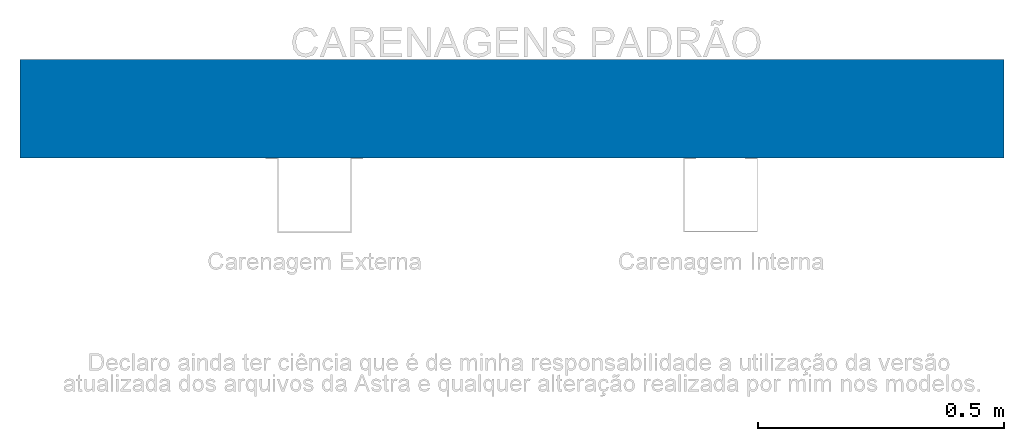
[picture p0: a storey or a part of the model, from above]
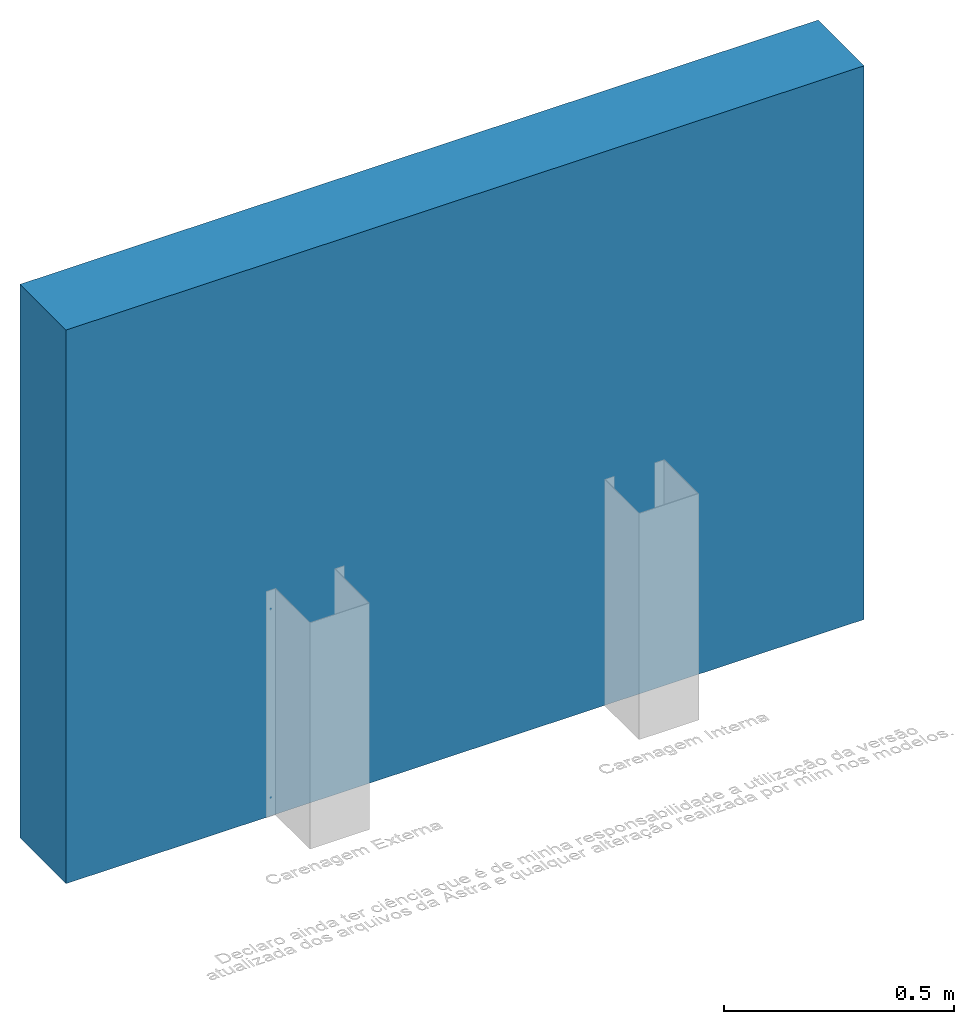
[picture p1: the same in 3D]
Properties of the parts of a building model (IFC2X3)

# File
Description: ViewDefinition [CoordinationView_V2.0]
File name: 0001
Time: 2025-07-10T16:41:57
Written by: The EXPRESS Data Manager Version 5.02.0100.07 : 28 Aug 2013
Made in: 21.0.0.383 - Exporter 21.0.0.383 - IU alternativa 21.0.0.383
Comment: STEP Physical File produced by: The EXPRESS Data Manager Version 5.02.0100.07 : 28 Aug 2013 * Module: EDMstepFileFactory/EDMstandAlone * Creation date: Thu Jul 10 16:41:57 2025 * Host: DNG1464 * Database: C:\Users\maria.cardoso\AppData\Local\Temp\3b02b41a-c4b6-4cdf-9117-29328b5b6a5f\55d656b9-dff8-46be-b086-2d08ecc8b85b\ifc * Database version: 5507 * Database creation date: Thu Jul 10 16:41:53 2025 * Schema: IFC2X3 * Model: DataRepository.ifc * Model creation date: Thu Jul 10 16:41:54 2025 * Header model: DataRepository.ifc_HeaderModel * Header model creation date: Thu Jul 10 16:41:54 2025 * EDMuser: sdai-user * EDMgroup: sdai-group * License ID and type: 5605 : Permanent license. Expiry date: * EDMstepFileFactory options: 020000

# IfcProject, 0001
LongName: Nome do projeto; Phase: Status do projeto

# IfcSite, Default
RefLatitude: -15, -52, 0, -120620; RefLongitude: -47, -55, 0, -114440; RefElevation: 0 mm

# IfcBuilding
Pset_BuildingCommon - NumberOfStoreys: 1

# IfcBuildingStorey: Nível:Cabeça de 8 mm, Vista Principal
LongName: Vista Principal; Elevation: 0 mm

# IfcBuildingElementProxy: Texto do modelo:600mm Arial (3)
In: Vista Principal
Type - Pset_BuildingElementProxyCommon - Reference: 600mm Arial
Type - Pset_QuantityTakeOff - Reference: 600mm Arial
Pset_BuildingElementProxyCommon - sets with these values: 2
Name (Texto do modelo:600mm Arial:...)
377453
377455
377750

# IfcBuildingElementProxy: Texto do modelo:TITULO, Texto do modelo:TITULO:377754
In: Vista Principal
Type - Pset_BuildingElementProxyCommon - Reference: TITULO
Type - Pset_QuantityTakeOff - Reference: TITULO
Pset_BuildingElementProxyCommon - sets with these values: 2
Pset_ProvisionForVoid - Shape: Undefined; Width: 150 mm; Depth: 150 mm

# IfcFlowTerminal: Carenagem - Aba Externa:Carenagem 600x150x150mm, Carenagem - Aba Externa:Carenagem 600x150x150mm:371474
In: Vista Principal
Type - Material: PS Branco
Type - Pset_ManufacturerTypeInformation - Manufacturer: Astra
Type - Pset_QuantityTakeOff - Reference: Carenagem 600x150x150mm
Pset_DistributionFlowElementCommon - Reference: Carenagem 600x150x150mm; sets with these values: 2

# IfcFlowTerminal: Carenagem - Aba Interna:Carenagem 600x150x150mm, Carenagem - Aba Interna:Carenagem 600x150x150mm:376178
In: Vista Principal
Type - Material: PS Branco
Type - Pset_ManufacturerTypeInformation - Manufacturer: Astra
Type - Pset_QuantityTakeOff - Reference: Carenagem 600x150x150mm
Pset_DistributionFlowElementCommon - Reference: Carenagem 600x150x150mm; sets with these values: 3
Pset_ManufacturerTypeInformation - sets with these values: 2

# IfcOpeningElement: Opening (4)
In: Vista Principal
Pset_ManufacturerTypeInformation - Manufacturer: Astra
Pset_OpeningElementCommon - Reference: Carenagem 600x150x150mm; sets with these values: 2
Name (Carenagem - Aba Externa:Carenagem 600x150x150mm:371474:...)
1
2
3
4

# IfcWallStandardCase: Parede básica:Genérico - 200 mm, Parede básica:Genérico - 200 mm:329028
In: Vista Principal
Type - PredefinedType: STANDARD; Material: Material pré-definido de parede 200 mm
Type - Pset_QuantityTakeOff - Reference: Genérico - 200 mm
Type - Pset_ReinforcementBarPitchOfWall - Reference: Genérico - 200 mm
Type - Pset_WallCommon - Reference: Genérico - 200 mm; IsExternal: no
Pset_QuantityTakeOff - sets with these values: 2
Pset_WallCommon - IsExternal: yes; ExtendToStructure: no; LoadBearing: no
